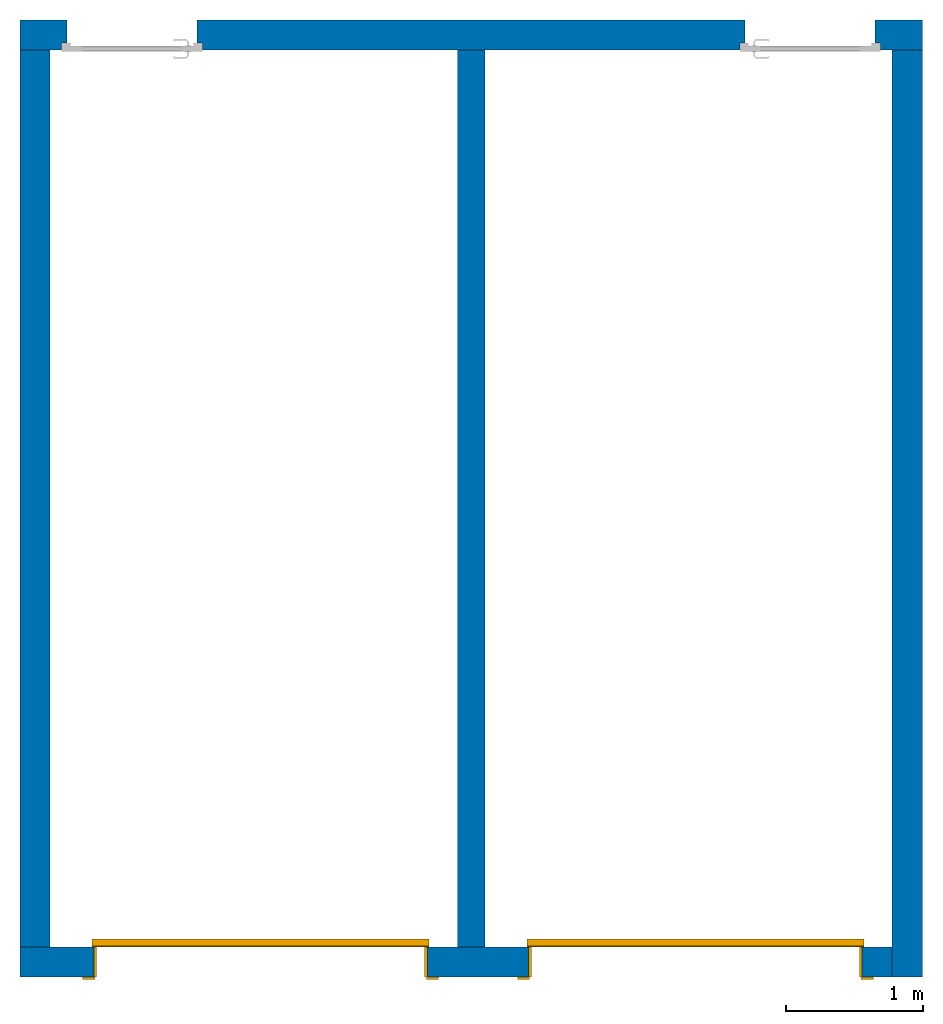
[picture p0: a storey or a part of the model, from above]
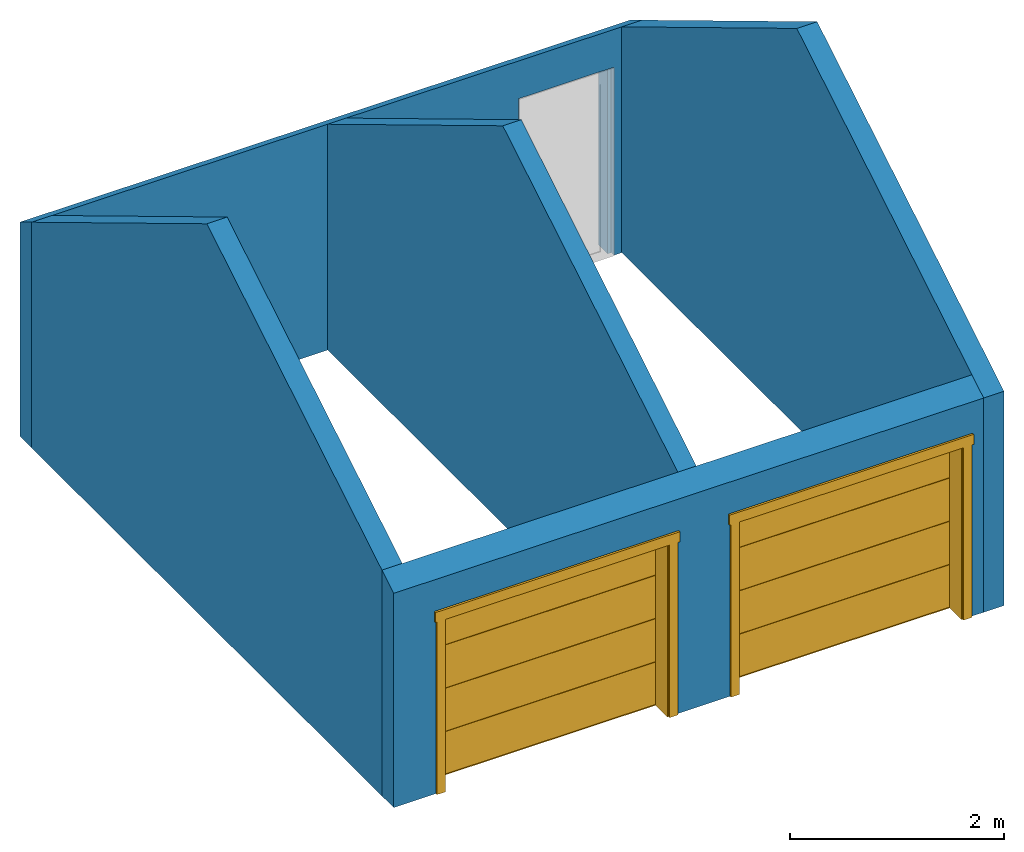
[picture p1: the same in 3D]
Properties of the parts of a building model (IFC2X3)

# File
Description: ViewDefinition [CoordinationView_V2.0]
Time: 2016-03-23T11:01:16
Written by: The EXPRESS Data Manager Version 5.02.0100.07 : 28 Aug 2013
Made in: 20150714_1515(x64) - Exporter 16.3.0.0 - Interface alternative d'export 16.3.0.0
Comment: STEP Physical File produced by: The EXPRESS Data Manager Version 5.02.0100.07 : 28 Aug 2013 * Module: EDMstepFileFactory/EDMstandAlone * Creation date: Wed Mar 23 11:01:16 2016 * Host: St�phaneBertran * Database: C:\Users\STPHAN~1\AppData\Local\Temp\{24B45148-9CD8-4A51-8CD9-05CDD8897D39}\ifc * Database version: 5507 * Database creation date: Wed Mar 23 11:01:13 2016 * Schema: IFC2X3 * Model: DataRepository.ifc * Model creation date: Wed Mar 23 11:01:14 2016 * Header model: DataRepository.ifc_HeaderModel * Header model creation date: Wed Mar 23 11:01:14 2016 * EDMuser: sdai-user * EDMgroup: sdai-group * License ID and type: 5605 : Permanent license. Expiry date: * EDMstepFileFactory options: 020000

# IfcProject
LongName: E:\02 Année scolaire 2015 2016\01 Seconde TEBEE\07 Projet Damparis\Travail demandé\Nouveau dossier\garage seul.ifc

# IfcSite, Surface:187648
RefLatitude: 48, 51, 23, 999632; RefLongitude: 2, 21, 3, 553904; RefElevation: 0 m

# IfcBuilding
Pset_BuildingCommon - NumberOfStoreys: 3

# IfcBuildingStorey (3)
Name | LongName | Elevation (m)
soubassement | soubassement | -0.6
Rez de chaussée | Rez de chaussée | 0
Plan étage | Plan étage | 2.74

# IfcSpace (2)
In: Rez de chaussée
InteriorOrExteriorSpace: INTERNAL
Name | LongName | Reference
1 | Garage 1 | Garage 1 1
2 | Garage 2 | Garage 2 2

# IfcDoor: 93 x 210 - (90), FR_PVC Panneau Plein:93 x 210 - (90):286378
In: Rez de chaussée
Type - OperationType: SINGLE_SWING_LEFT; ParameterTakesPrecedence: no; Sizeable: no; Material: Poignée PVC, PVC Blanc
Type - FR_PVC Panneau Plein:93 x 210 - (90):286378 - PanelOperation: SWINGING
OverallHeight: 2.15 m; OverallWidth: 1.03 m
Pset_DoorCommon - IsExternal: no; Reference: 93 x 210 - (90)

# IfcDoor: 93 x 210 - (90), FR_PVC Panneau Plein:93 x 210 - (90):286377
In: Rez de chaussée
Type - OperationType: SINGLE_SWING_RIGHT; ParameterTakesPrecedence: no; Sizeable: no; Material: Poignée PVC, PVC Blanc
Type - FR_PVC Panneau Plein:93 x 210 - (90):286377 - PanelOperation: SWINGING
OverallHeight: 2.15 m; OverallWidth: 1.03 m
Pset_DoorCommon - IsExternal: no; Reference: 93 x 210 - (90)

# IfcDoor: 96" x 78" (2)
In: Rez de chaussée
Type - ParameterTakesPrecedence: no; Sizeable: no; Classification: B2030410 Overhead Doors (Uniformat); Material: Rubber - Black
OverallHeight: 1.9812 m; OverallWidth: 2.4384 m
Pset_DoorCommon - IsExternal: no; Reference: 96" x 78"
Name (Overhead-Sectional-Flush:96" x 78":...)
286375
286376

# IfcRoof: Toit de base:Toit - 100 mm 2, Toit de base:Toit - 100 mm 2:286381
In: Plan étage
Pset_RoofCommon - IsExternal: yes; Reference: Toit - 100 mm 2; TotalArea: 61.8782 m2; ProjectedArea: 53.04 m2

# IfcSlab: Sol:Dalle en béton - 250 mm, Sol:Dalle en béton - 250 mm:286388
In: soubassement
PredefinedType: FLOOR; Material: Maçonnerie - Béton 0.25 m
Pset_SlabCommon - IsExternal: no; LoadBearing: yes; Reference: Dalle en béton - 250 mm; PitchAngle: 0 deg

# IfcSlab: Toit de base:Toit - 100 mm 2 (2)
In: Plan étage
PredefinedType: ROOF; Material: Toit par défaut 0.1 m
Pset_SlabCommon - IsExternal: yes; Reference: Toit - 100 mm 2; LoadBearing: yes; PitchAngle: 31 deg

# IfcStair: Escalier:Monobloc:28673, Escalier:Monobloc:223436
In: Rez de chaussée
Pset_StairCommon - Reference: Monobloc; IsExternal: no; NumberOfRiser: 12; NumberOfTreads: 12; RiserHeight: 0.182667 m; TreadLength: 0.264667 m

# IfcWallStandardCase: Mur de base:Ext.BBM + enduit 22 (4)
In: Rez de chaussée
Type - PredefinedType: STANDARD; Material: Maçonnerie - Enduit 0.02 m, Maçonnerie - Béton 0.2 m
Pset_WallCommon - Reference: Ext.BBM + enduit 22; LoadBearing: no; ExtendToStructure: yes; IsExternal: yes
Name (Mur de base:Ext.BBM + enduit 22:...)
286370
286371
286372
286373

# IfcWallStandardCase: Mur de base:Ext.BBM 20 cm, Mur de base:Ext.BBM 20 cm:286374
In: Rez de chaussée
Type - PredefinedType: STANDARD; Material: Mur par défaut 0.2 m
Pset_WallCommon - LoadBearing: no; ExtendToStructure: yes; IsExternal: yes; Reference: Ext.BBM 20 cm

# IfcWallStandardCase: Mur de base:fond 60 cm (4)
In: soubassement
Type - PredefinedType: STANDARD; Material: FONDATIONS 0.6 m
Pset_WallCommon - IsExternal: yes; LoadBearing: yes; Reference: fond 60 cm; ExtendToStructure: no
Name (Mur de base:fond 60 cm:...)
286395
286397
286399
286401
